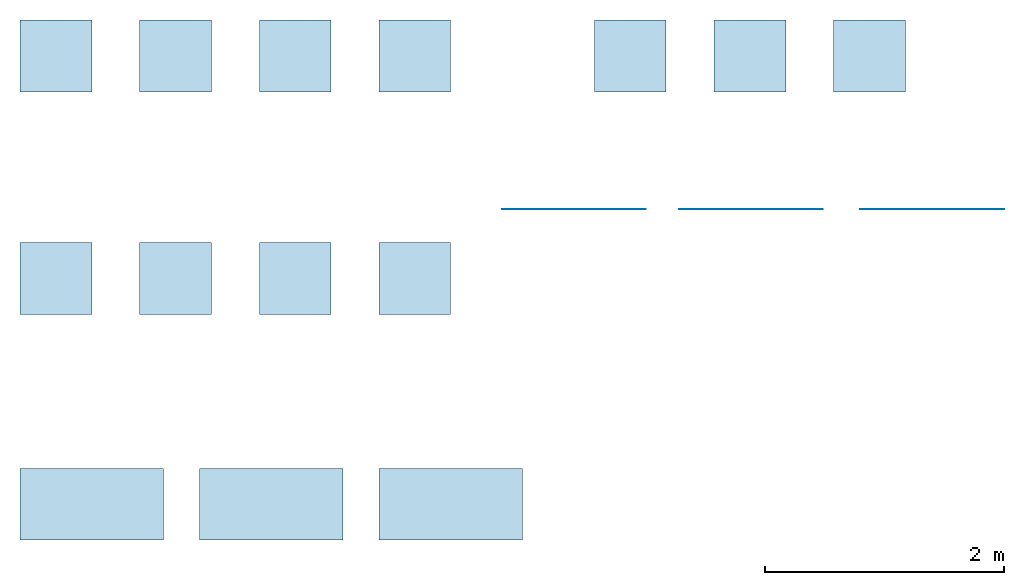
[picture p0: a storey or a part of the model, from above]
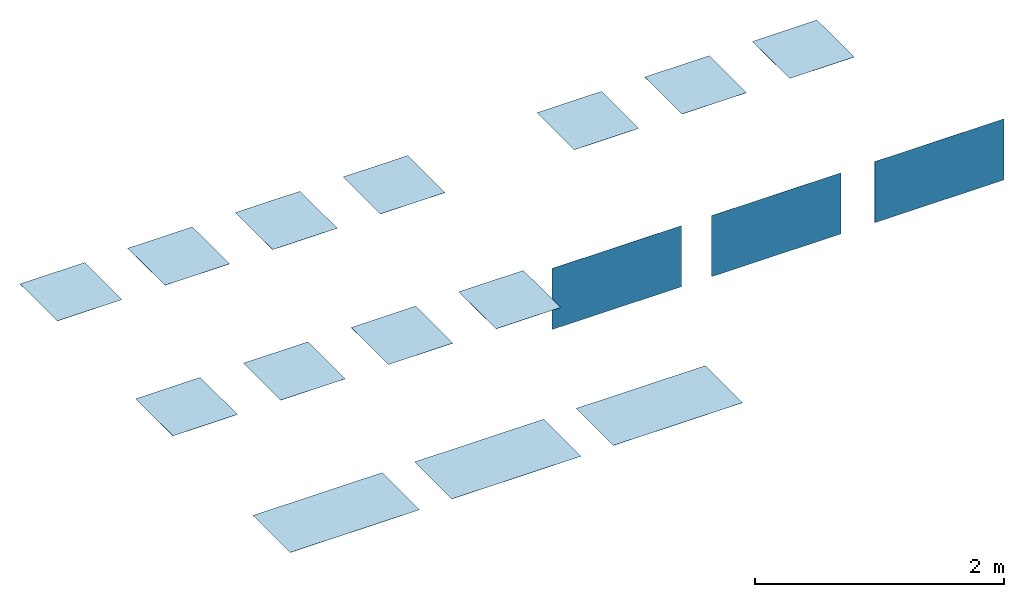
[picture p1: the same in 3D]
Properties of the parts of a building model (IFC2X3)

# File
Description: ViewDefinition [CoordinationView_V2.0]
File name: Número de proyecto
Time: 2018-05-15T15:33:24
Written by: The EXPRESS Data Manager Version 5.02.0100.07 : 28 Aug 2013
Made in: 20140606_1530(x64) - Exporter 15.7.0.0 - Alternate UI 15.7.0.0
Comment: STEP Physical File produced by: The EXPRESS Data Manager Version 5.02.0100.07 : 28 Aug 2013 * Module: EDMstepFileFactory/EDMstandAlone * Creation date: Tue May 15 15:33:24 2018 * Host: WEB2 * Database: C:\Users\webpc2\AppData\Local\Temp\{D7DBF2E8-4DE5-4315-ADB8-9A0519E80F4D}\ifc * Database version: 5507 * Database creation date: Tue May 15 15:33:23 2018 * Schema: IFC2X3 * Model: DataRepository.ifc * Model creation date: Tue May 15 15:33:23 2018 * Header model: DataRepository.ifc_HeaderModel * Header model creation date: Tue May 15 15:33:23 2018 * EDMuser: sdai-user * EDMgroup: sdai-group * License ID and type: 5605 : Permanent license. Expiry date: * EDMstepFileFactory options: 020000

# IfcProject, Número de proyecto
LongName: Nombre de proyecto; Phase: Estado de proyecto

# IfcSite, Default
RefLatitude: 40, 25, 0, 86975; RefLongitude: -3, -42, -1, -243858; RefElevation: 0 m

# IfcBuilding
Pset_BuildingCommon - NumberOfStoreys: 2

# IfcBuildingStorey (2)
Name | LongName | Elevation (m)
CEPPO DI GRE FLOOR TILES | CEPPO DI GRE FLOOR TILES | 0
Nivel 2 | Nivel 2 | 3

# IfcSlab: Suelo:VIVES - CEPPO DI GRE CEMENTO 60x60, Suelo:VIVES - CEPPO DI GRE CEMENTO 60x60:212779
In: CEPPO DI GRE FLOOR TILES
PredefinedType: FLOOR; Material: VIVES CEPPO DI GRE CEMENTO 60x60 0.001 m
Pset_SlabCommon - LoadBearing: no; IsExternal: no; Reference: VIVES - CEPPO DI GRE CEMENTO 60x60; ThermalTransmittance: 1500 kg/K/s3; PitchAngle: 0 deg
Pset_ManufacturerTypeInformation - Manufacturer: VIVES Azulejos y Gres S.A.

# IfcSlab: Suelo:VIVES - CEPPO DI GRE GRIS 60x60, Suelo:VIVES - CEPPO DI GRE GRIS 60x60:213871
In: CEPPO DI GRE FLOOR TILES
PredefinedType: FLOOR; Material: VIVES CEPPO DI GRE GRIS 60x60 0.001 m
Pset_SlabCommon - LoadBearing: no; IsExternal: no; PitchAngle: 0 deg; Reference: VIVES - CEPPO DI GRE GRIS 60x60; ThermalTransmittance: 1500 kg/K/s3
Pset_ManufacturerTypeInformation - Manufacturer: VIVES Azulejos y Gres S.A.

# IfcSlab: Suelo:VIVES - CEPPO DI GRE MARFIL 60x60, Suelo:VIVES - CEPPO DI GRE MARFIL 60x60:214131
In: CEPPO DI GRE FLOOR TILES
PredefinedType: FLOOR; Material: VIVES CEPPO DI GRE MARFIL 60x60 0.001 m
Pset_SlabCommon - LoadBearing: no; IsExternal: no; PitchAngle: 0 deg; Reference: VIVES - CEPPO DI GRE MARFIL 60x60; ThermalTransmittance: 1500 kg/K/s3
Pset_ManufacturerTypeInformation - Manufacturer: VIVES Azulejos y Gres S.A.

# IfcSlab: Suelo:VIVES - CEPPO DI GRE-R CEMENTO 59.3x119.3, Suelo:VIVES - CEPPO DI GRE-R CEMENTO 59.3x119.3:214422
In: CEPPO DI GRE FLOOR TILES
PredefinedType: FLOOR; Material: VIVES CEPPO DI GRE-R CEMENTO 59.3x119.3 0.0011 m
Pset_SlabCommon - LoadBearing: no; IsExternal: no; PitchAngle: 0 deg; Reference: VIVES - CEPPO DI GRE-R CEMENTO 59.3x119.3; ThermalTransmittance: 1363.64 kg/K/s3
Pset_ManufacturerTypeInformation - Manufacturer: VIVES Azulejos y Gres S.A.

# IfcSlab: Suelo:VIVES - CEPPO DI GRE-R CEMENTO 59.3x59.3, Suelo:VIVES - CEPPO DI GRE-R CEMENTO 59.3x59.3:214196
In: CEPPO DI GRE FLOOR TILES
PredefinedType: FLOOR; Material: VIVES CEPPO DI GRE-R CEMENTO 59.3x59.3 0.001 m
Pset_SlabCommon - LoadBearing: no; IsExternal: no; PitchAngle: 0 deg; Reference: VIVES - CEPPO DI GRE-R CEMENTO 59.3x59.3; ThermalTransmittance: 1500 kg/K/s3
Pset_ManufacturerTypeInformation - Manufacturer: VIVES Azulejos y Gres S.A.

# IfcSlab: Suelo:VIVES - CEPPO DI GRE-R GRIS 59.3x119.3, Suelo:VIVES - CEPPO DI GRE-R GRIS 59.3x119.3:214535
In: CEPPO DI GRE FLOOR TILES
PredefinedType: FLOOR; Material: VIVES CEPPO DI GRE-R GRIS 59.3x119.3 0.0011 m
Pset_SlabCommon - LoadBearing: no; IsExternal: no; PitchAngle: 0 deg; Reference: VIVES - CEPPO DI GRE-R GRIS 59.3x119.3; ThermalTransmittance: 1363.64 kg/K/s3
Pset_ManufacturerTypeInformation - Manufacturer: VIVES Azulejos y Gres S.A.

# IfcSlab: Suelo:VIVES - CEPPO DI GRE-R GRIS 59.3x59.3, Suelo:VIVES - CEPPO DI GRE-R GRIS 59.3x59.3:214204
In: CEPPO DI GRE FLOOR TILES
PredefinedType: FLOOR; Material: VIVES CEPPO DI GRE-R GRIS 59.3x59.3 0.001 m
Pset_SlabCommon - LoadBearing: no; IsExternal: no; PitchAngle: 0 deg; Reference: VIVES - CEPPO DI GRE-R GRIS 59.3x59.3; ThermalTransmittance: 1500 kg/K/s3
Pset_ManufacturerTypeInformation - Manufacturer: VIVES Azulejos y Gres S.A.

# IfcSlab: Suelo:VIVES - CEPPO DI GRE-R MARFIL 59.3x119.3, Suelo:VIVES - CEPPO DI GRE-R MARFIL 59.3x119.3:214548
In: CEPPO DI GRE FLOOR TILES
PredefinedType: FLOOR; Material: VIVES CEPPO DI GRE-R MARFIL 59.3x119.3 0.0011 m
Pset_SlabCommon - LoadBearing: no; IsExternal: no; PitchAngle: 0 deg; Reference: VIVES - CEPPO DI GRE-R MARFIL 59.3x119.3; ThermalTransmittance: 1363.64 kg/K/s3
Pset_ManufacturerTypeInformation - Manufacturer: VIVES Azulejos y Gres S.A.

# IfcSlab: Suelo:VIVES - CEPPO DI GRE-R MARFIL 59.3x59.3, Suelo:VIVES - CEPPO DI GRE-R MARFIL 59.3x59.3:214212
In: CEPPO DI GRE FLOOR TILES
PredefinedType: FLOOR; Material: VIVES CEPPO DI GRE-R MARFIL 59.3x59.3 0.001 m
Pset_SlabCommon - LoadBearing: no; IsExternal: no; PitchAngle: 0 deg; Reference: VIVES - CEPPO DI GRE-R MARFIL 59.3x59.3; ThermalTransmittance: 1500 kg/K/s3
Pset_ManufacturerTypeInformation - Manufacturer: VIVES Azulejos y Gres S.A.

# IfcSlab: Suelo:VIVES - MOS. AYMARAS CEMENTO 24.2x39.5, Suelo:VIVES - MOS. AYMARAS CEMENTO 24.2x39.5:214335
In: CEPPO DI GRE FLOOR TILES
PredefinedType: FLOOR; Material: VIVES MOSAICO AYMARAS CEMENTO 24.2x39.5 0.001 m
Pset_SlabCommon - LoadBearing: no; IsExternal: no; PitchAngle: 0 deg; Reference: VIVES - MOS. AYMARAS CEMENTO 24.2x39.5; ThermalTransmittance: 1500 kg/K/s3
Pset_ManufacturerTypeInformation - Manufacturer: VIVES Azulejos y Gres S.A.

# IfcSlab: Suelo:VIVES - MOS. AYMARAS GRIS 24.2x39.5, Suelo:VIVES - MOS. AYMARAS GRIS 24.2x39.5:214343
In: CEPPO DI GRE FLOOR TILES
PredefinedType: FLOOR; Material: VIVES MOSAICO AYMARAS GRIS 24.2x39.5 0.001 m
Pset_SlabCommon - LoadBearing: no; IsExternal: no; PitchAngle: 0 deg; Reference: VIVES - MOS. AYMARAS GRIS 24.2x39.5; ThermalTransmittance: 1500 kg/K/s3
Pset_ManufacturerTypeInformation - Manufacturer: VIVES Azulejos y Gres S.A.

# IfcSlab: Suelo:VIVES - MOS. AYMARAS MARFIL 24.2x39.5, Suelo:VIVES - MOS. AYMARAS MARFIL 24.2x39.5:214351
In: CEPPO DI GRE FLOOR TILES
PredefinedType: FLOOR; Material: VIVES MOSAICO AYMARAS MARFIL 24.2x39.5 0.001 m
Pset_SlabCommon - LoadBearing: no; IsExternal: no; PitchAngle: 0 deg; Reference: VIVES - MOS. AYMARAS MARFIL 24.2x39.5; ThermalTransmittance: 1500 kg/K/s3
Pset_ManufacturerTypeInformation - Manufacturer: VIVES Azulejos y Gres S.A.

# IfcSlab: Suelo:VIVES - ORIYAS NATURAL 60x60, Suelo:VIVES - ORIYAS NATURAL 60x60:214159
In: CEPPO DI GRE FLOOR TILES
PredefinedType: FLOOR; Material: VIVES ORIYAS NATURAL 60x60 0.001 m
Pset_SlabCommon - LoadBearing: no; IsExternal: no; PitchAngle: 0 deg; Reference: VIVES - ORIYAS NATURAL 60x60; ThermalTransmittance: 1500 kg/K/s3
Pset_ManufacturerTypeInformation - Manufacturer: VIVES Azulejos y Gres S.A.

# IfcSlab: Suelo:VIVES - ORIYAS-R NATURAL 59.3x59.3, Suelo:VIVES - ORIYAS-R NATURAL 59.3x59.3:214220
In: CEPPO DI GRE FLOOR TILES
PredefinedType: FLOOR; Material: VIVES ORIYAS-R NATURAL 59.3x59.3 0.001 m
Pset_SlabCommon - LoadBearing: no; IsExternal: no; PitchAngle: 0 deg; Reference: VIVES - ORIYAS-R NATURAL 59.3x59.3; ThermalTransmittance: 1500 kg/K/s3
Pset_ManufacturerTypeInformation - Manufacturer: VIVES Azulejos y Gres S.A.

# IfcWallStandardCase: Muro básico:VIVES CEPPO DI GRE CEMENTO 60x60, Muro básico:VIVES CEPPO DI GRE CEMENTO 60x60:211391
In: Nivel 2
Type - PredefinedType: STANDARD; Material: VIVES CEPPO DI GRE CEMENTO 60x60 0.001 m
Pset_WallCommon - LoadBearing: no; ExtendToStructure: no; IsExternal: no; Reference: VIVES CEPPO DI GRE CEMENTO 60x60; ThermalTransmittance: 1500 kg/K/s3
Pset_ManufacturerTypeInformation - Manufacturer: VIVES Azulejos y Gres S.A.

# IfcWallStandardCase: Muro básico:VIVES CEPPO DI GRE GRIS 60x60, Muro básico:VIVES CEPPO DI GRE GRIS 60x60:211392
In: Nivel 2
Type - PredefinedType: STANDARD; Material: VIVES CEPPO DI GRE GRIS 60x60 0.001 m
Pset_WallCommon - LoadBearing: no; ExtendToStructure: no; IsExternal: no; Reference: VIVES CEPPO DI GRE GRIS 60x60; ThermalTransmittance: 1500 kg/K/s3
Pset_ManufacturerTypeInformation - Manufacturer: VIVES Azulejos y Gres S.A.

# IfcWallStandardCase: Muro básico:VIVES CEPPO DI GRE MARFIL 60x60, Muro básico:VIVES CEPPO DI GRE MARFIL 60x60:211393
In: Nivel 2
Type - PredefinedType: STANDARD; Material: VIVES CEPPO DI GRE MARFIL 60x60 0.001 m
Pset_WallCommon - LoadBearing: no; ExtendToStructure: no; IsExternal: no; Reference: VIVES CEPPO DI GRE MARFIL 60x60; ThermalTransmittance: 1500 kg/K/s3
Pset_ManufacturerTypeInformation - Manufacturer: VIVES Azulejos y Gres S.A.

# IfcWallStandardCase: Muro básico:VIVES CEPPO DI GRE-R CEMENTO 59.3x119.3, Muro básico:VIVES CEPPO DI GRE-R CEMENTO 59.3x119.3:211363
In: CEPPO DI GRE FLOOR TILES
Type - PredefinedType: STANDARD; Material: VIVES CEPPO DI GRE-R CEMENTO 59.3x119.3 0.0011 m
Pset_WallCommon - Reference: VIVES CEPPO DI GRE-R CEMENTO 59.3x119.3; LoadBearing: no; ExtendToStructure: no; IsExternal: no; ThermalTransmittance: 1363.64 kg/K/s3
Pset_ManufacturerTypeInformation - Manufacturer: VIVES Azulejos y Gres S.A.

# IfcWallStandardCase: Muro básico:VIVES CEPPO DI GRE-R CEMENTO 59.3x59.3, Muro básico:VIVES CEPPO DI GRE-R CEMENTO 59.3x59.3:211442
In: Nivel 2
Type - PredefinedType: STANDARD; Material: VIVES CEPPO DI GRE-R CEMENTO 59.3x59.3 0.001 m
Pset_WallCommon - LoadBearing: no; ExtendToStructure: no; IsExternal: no; Reference: VIVES CEPPO DI GRE-R CEMENTO 59.3x59.3; ThermalTransmittance: 1500 kg/K/s3
Pset_ManufacturerTypeInformation - Manufacturer: VIVES Azulejos y Gres S.A.

# IfcWallStandardCase: Muro básico:VIVES CEPPO DI GRE-R GRIS 59.3x119.3, Muro básico:VIVES CEPPO DI GRE-R GRIS 59.3x119.3:211364
In: CEPPO DI GRE FLOOR TILES
Type - PredefinedType: STANDARD; Material: VIVES CEPPO DI GRE-R GRIS 59.3x119.3 0.001 m
Pset_WallCommon - LoadBearing: no; ExtendToStructure: no; IsExternal: no; Reference: VIVES CEPPO DI GRE-R GRIS 59.3x119.3; ThermalTransmittance: 1500 kg/K/s3
Pset_ManufacturerTypeInformation - Manufacturer: VIVES Azulejos y Gres S.A.

# IfcWallStandardCase: Muro básico:VIVES CEPPO DI GRE-R GRIS 59.3x59.3, Muro básico:VIVES CEPPO DI GRE-R GRIS 59.3x59.3:211443
In: Nivel 2
Type - PredefinedType: STANDARD; Material: VIVES CEPPO DI GRE-R GRIS 59.3x59.3 0.001 m
Pset_WallCommon - LoadBearing: no; ExtendToStructure: no; IsExternal: no; Reference: VIVES CEPPO DI GRE-R GRIS 59.3x59.3; ThermalTransmittance: 1500 kg/K/s3
Pset_ManufacturerTypeInformation - Manufacturer: VIVES Azulejos y Gres S.A.

# IfcWallStandardCase: Muro básico:VIVES CEPPO DI GRE-R MARFIL 59.3x119.3, Muro básico:VIVES CEPPO DI GRE-R MARFIL 59.3x119.3:211365
In: CEPPO DI GRE FLOOR TILES
Type - PredefinedType: STANDARD; Material: VIVES CEPPO DI GRE-R MARFIL 59.3x119.3 0.001 m
Pset_WallCommon - LoadBearing: no; ExtendToStructure: no; IsExternal: no; Reference: VIVES CEPPO DI GRE-R MARFIL 59.3x119.3; ThermalTransmittance: 1500 kg/K/s3
Pset_ManufacturerTypeInformation - Manufacturer: VIVES Azulejos y Gres S.A.

# IfcWallStandardCase: Muro básico:VIVES CEPPO DI GRE-R MARFIL 59.3x59.3, Muro básico:VIVES CEPPO DI GRE-R MARFIL 59.3x59.3:211444
In: Nivel 2
Type - PredefinedType: STANDARD; Material: VIVES CEPPO DI GRE-R MARFIL 59.3x59.3 0.001 m
Pset_WallCommon - LoadBearing: no; ExtendToStructure: no; IsExternal: no; Reference: VIVES CEPPO DI GRE-R MARFIL 59.3x59.3; ThermalTransmittance: 1500 kg/K/s3
Pset_ManufacturerTypeInformation - Manufacturer: VIVES Azulejos y Gres S.A.

# IfcWallStandardCase: Muro básico:VIVES MOS. AYMARAS CEMENTO 24.2x39.5, Muro básico:VIVES MOS. AYMARAS CEMENTO 24.2x39.5:211854
In: Nivel 2
Type - PredefinedType: STANDARD; Material: VIVES MOSAICO AYMARAS CEMENTO 24.2x39.5 0.001 m
Pset_WallCommon - LoadBearing: no; ExtendToStructure: no; IsExternal: no; Reference: VIVES MOS. AYMARAS CEMENTO 24.2x39.5; ThermalTransmittance: 1500 kg/K/s3
Pset_ManufacturerTypeInformation - Manufacturer: VIVES Azulejos y Gres S.A.

# IfcWallStandardCase: Muro básico:VIVES MOS. AYMARAS GRIS 24.2x39.5, Muro básico:VIVES MOS. AYMARAS GRIS 24.2x39.5:211994
In: Nivel 2
Type - PredefinedType: STANDARD; Material: VIVES MOSAICO AYMARAS GRIS 24.2x39.5 0.001 m
Pset_WallCommon - LoadBearing: no; ExtendToStructure: no; IsExternal: no; Reference: VIVES MOS. AYMARAS GRIS 24.2x39.5; ThermalTransmittance: 1500 kg/K/s3
Pset_ManufacturerTypeInformation - Manufacturer: VIVES Azulejos y Gres S.A.

# IfcWallStandardCase: Muro básico:VIVES MOS. AYMARAS MARFIL 24.2x39.5, Muro básico:VIVES MOS. AYMARAS MARFIL 24.2x39.5:212035
In: Nivel 2
Type - PredefinedType: STANDARD; Material: VIVES MOSAICO AYMARAS MARFIL 24.2x39.5 0.001 m
Pset_WallCommon - LoadBearing: no; ExtendToStructure: no; IsExternal: no; Reference: VIVES MOS. AYMARAS MARFIL 24.2x39.5; ThermalTransmittance: 1500 kg/K/s3
Pset_ManufacturerTypeInformation - Manufacturer: VIVES Azulejos y Gres S.A.

# IfcWallStandardCase: Muro básico:VIVES ORIYAS NATURAL 60x60, Muro básico:VIVES ORIYAS NATURAL 60x60:211394
In: Nivel 2
Type - PredefinedType: STANDARD; Material: VIVES ORIYAS NATURAL 60x60 0.001 m
Pset_WallCommon - LoadBearing: no; ExtendToStructure: no; IsExternal: no; Reference: VIVES ORIYAS NATURAL 60x60; ThermalTransmittance: 1500 kg/K/s3
Pset_ManufacturerTypeInformation - Manufacturer: VIVES Azulejos y Gres S.A.

# IfcWallStandardCase: Muro básico:VIVES ORIYAS-R NATURAL 59.3x59.3, Muro básico:VIVES ORIYAS-R NATURAL 59.3x59.3:211445
In: Nivel 2
Type - PredefinedType: STANDARD; Material: VIVES ORIYAS-R NATURAL 59.3x59.3 0.001 m
Pset_WallCommon - LoadBearing: no; ExtendToStructure: no; IsExternal: no; Reference: VIVES ORIYAS-R NATURAL 59.3x59.3; ThermalTransmittance: 1500 kg/K/s3
Pset_ManufacturerTypeInformation - Manufacturer: VIVES Azulejos y Gres S.A.
